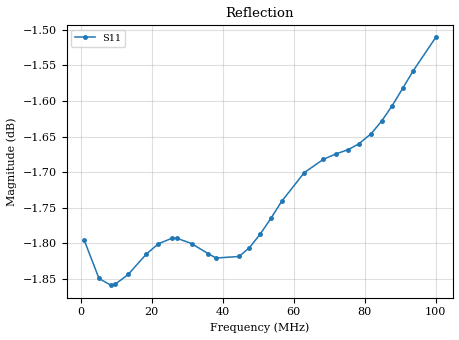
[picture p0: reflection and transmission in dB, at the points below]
# MHz S RI R 50.0
! SimSmith 18.4g
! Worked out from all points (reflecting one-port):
!   1000 points, 1 MHz to 100 MHz, reference 50 ohm
!   lowest |S11| = -1.9 dB at 8.432 MHz (marker M1), VSWR 9.38, Z = 9.4 + j43.3 ohm
!   phase of S11 starts at 170 deg and turns -956 deg over the sweep
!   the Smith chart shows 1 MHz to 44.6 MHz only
!   S11 on the Smith chart (normalised r, x): 1 MHz: 0.10, +0.09; 9.721 MHz: 0.23, +1.07; 18.54 MHz: 9.53, -0.84; 27.26 MHz: 0.22, -1.05; 35.88 MHz: 0.10, -0.09; 44.6 MHz: 0.16, +0.74
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1  -0.8007 0.1423
5.162162  -0.5089 0.6279
8.432432  -0.0995 0.8012
9.720721  0.0769 0.8038
13.38739  0.5317 0.6094
18.54054  0.8113 -0.015
21.90991  0.6761 -0.4511
25.77478  0.2622 -0.7701
27.26126  0.062 -0.8111
31.22522  -0.4565 -0.6725
35.88288  -0.7979 -0.1478
38.16216  -0.7941 0.1642
44.6036  -0.22 0.7807
47.47748  0.1702 0.7942
50.54955  0.5424 0.607
53.62162  0.7736 0.2601
56.59459  0.8058 -0.1428
62.93694  0.2664 -0.7778
68.28829  -0.4441 -0.694
71.95495  -0.7642 -0.31
75.32432  -0.8118 0.1483
78.2973  -0.6425 0.5191
81.86486  -0.2394 0.792
84.73874  0.1541 0.8146
87.71171  0.5245 0.6447
90.78378  0.7753 0.3061
93.65766  0.8315 -0.085
100  0.3391 -0.7689
